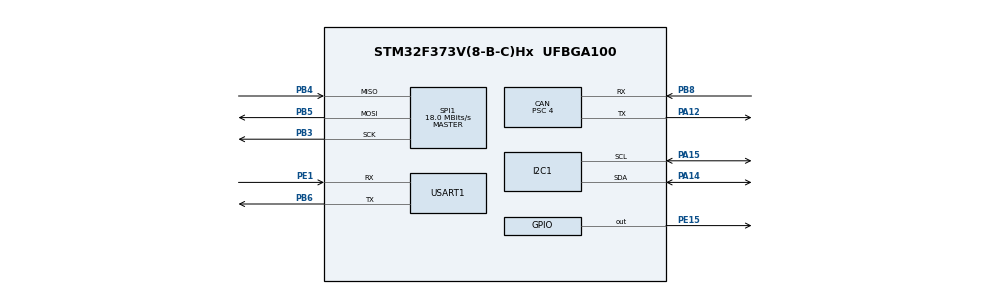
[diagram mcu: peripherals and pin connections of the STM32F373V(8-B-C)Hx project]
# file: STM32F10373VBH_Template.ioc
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CAN.BS1=CAN_BS1_5TQ
CAN.BS2=CAN_BS2_3TQ
CAN.CalculateBaudRate=1000000
CAN.CalculateTimeBit=999.99
CAN.CalculateTimeQuantum=111.11111111111111
CAN.Prescaler=4
Mcu.Family=STM32F3
Mcu.Name=STM32F373V(8-B-C)Hx
Mcu.Package=UFBGA100
NVIC.CAN_RX0_IRQn=true\:0\:0\:false\:false\:true\:true\:true
NVIC.PriorityGroup=NVIC_PRIORITYGROUP_4
NVIC.TIM2_IRQn=true\:0\:0\:false\:false\:true\:true\:true
NVIC.USART1_IRQn=true\:0\:0\:false\:false\:true\:true\:true
PA12.Mode=CAN_Activate
PA12.Signal=CAN_TX
PA14.Mode=I2C
PA14.Signal=I2C1_SDA
PA15.Mode=I2C
PA15.Signal=I2C1_SCL
PB3.Mode=Full_Duplex_Master
PB3.Signal=SPI1_SCK
PB4.Mode=Full_Duplex_Master
PB4.Signal=SPI1_MISO
PB5.Mode=Full_Duplex_Master
PB5.Signal=SPI1_MOSI
PB6.Mode=Asynchronous
PB6.Signal=USART1_TX
PB8.Mode=CAN_Activate
PB8.Signal=CAN_RX
PE1.Mode=Asynchronous
PE1.Signal=USART1_RX
PE15.GPIO_Speed=GPIO_SPEED_FREQ_HIGH
PE15.Signal=GPIO_Output
PF0-OSC_IN.Mode=HSE-External-Oscillator
PF0-OSC_IN.Signal=RCC_OSC_IN
PF1-OSC_OUT.Mode=HSE-External-Oscillator
PF1-OSC_OUT.Signal=RCC_OSC_OUT
ProjectManager.HeapSize=0x200
ProjectManager.StackSize=0x400
ProjectManager.TargetToolchain=Makefile
RCC.AHBFreq_Value=72000000
RCC.APB1CLKDivider=RCC_HCLK_DIV2
RCC.APB1Freq_Value=36000000
RCC.APB1TimFreq_Value=72000000
RCC.APB2Freq_Value=36000000
RCC.APB2TimFreq_Value=72000000
RCC.CortexFreq_Value=72000000
RCC.HCLKFreq_Value=72000000
RCC.HSE_VALUE=8000000
RCC.HSI_VALUE=8000000
RCC.LSE_VALUE=32768
RCC.PLLMUL=RCC_PLL_MUL9
RCC.PLLSourceVirtual=RCC_PLLSOURCE_HSE
RCC.SYSCLKFreq_VALUE=72000000
RCC.SYSCLKSource=RCC_SYSCLKSOURCE_PLLCLK
RCC.USBFreq_Value=72000000
SPI1.CalculateBaudRate=18.0 MBits/s
SPI1.Direction=SPI_DIRECTION_2LINES
SPI1.Mode=SPI_MODE_MASTER
SPI1.VirtualType=VM_MASTER
TIM2.Period=999
TIM2.Prescaler=35
USART1.VirtualMode-Asynchronous=VM_ASYNC
VP_TIM2_VS_ClockSourceINT.Mode=Internal
board=custom

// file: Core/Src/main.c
/* USER CODE BEGIN Header */
/**
  ******************************************************************************
  * @file           : main.c
  * @brief          : Main program body
  ******************************************************************************
  * @attention
  *
  * <h2><center>&copy; Copyright (c) 2021 STMicroelectronics.
  * All rights reserved.</center></h2>
  *
  * This software component is licensed by ST under BSD 3-Clause license,
  * the "License"; You may not use this file except in compliance with the
  * License. You may obtain a copy of the License at:
  *                        opensource.org/licenses/BSD-3-Clause
  *
  ******************************************************************************
  */
/* USER CODE END Header */
#include "main.h"

CAN_HandleTypeDef hcan;

I2C_HandleTypeDef hi2c1;

SPI_HandleTypeDef hspi1;

TIM_HandleTypeDef htim2;

UART_HandleTypeDef huart1;

void SystemClock_Config(void);
static void MX_GPIO_Init(void);
static void MX_CAN_Init(void);
static void MX_I2C1_Init(void);
static void MX_SPI1_Init(void);
static void MX_TIM2_Init(void);
static void MX_USART1_UART_Init(void);

int main(void)
{

  /* MCU Configuration--------------------------------------------------------*/

  /* Reset of all peripherals, Initializes the Flash interface and the Systick. */
  HAL_Init();

  /* Configure the system clock */
  SystemClock_Config();

  /* Initialize all configured peripherals */
  MX_GPIO_Init();
  MX_CAN_Init();
  MX_I2C1_Init();
  MX_SPI1_Init();
  MX_TIM2_Init();
  MX_USART1_UART_Init();

  /* Infinite loop */
  while (1)
  {

  }
}

void SystemClock_Config(void)
{
  RCC_OscInitTypeDef RCC_OscInitStruct = {0};
  RCC_ClkInitTypeDef RCC_ClkInitStruct = {0};
  RCC_PeriphCLKInitTypeDef PeriphClkInit = {0};

  /** Initializes the RCC Oscillators according to the specified parameters
  * in the RCC_OscInitTypeDef structure.
  */
  RCC_OscInitStruct.OscillatorType = RCC_OSCILLATORTYPE_HSI|RCC_OSCILLATORTYPE_HSE;
  RCC_OscInitStruct.HSEState = RCC_HSE_ON;
  RCC_OscInitStruct.HSEPredivValue = RCC_HSE_PREDIV_DIV1;
  RCC_OscInitStruct.HSIState = RCC_HSI_ON;
  RCC_OscInitStruct.HSICalibrationValue = RCC_HSICALIBRATION_DEFAULT;
  RCC_OscInitStruct.PLL.PLLState = RCC_PLL_ON;
  RCC_OscInitStruct.PLL.PLLSource = RCC_PLLSOURCE_HSE;
  RCC_OscInitStruct.PLL.PLLMUL = RCC_PLL_MUL9;
  if (HAL_RCC_OscConfig(&RCC_OscInitStruct) != HAL_OK)
  {
    Error_Handler();
  }
  /** Initializes the CPU, AHB and APB buses clocks
  */
  RCC_ClkInitStruct.ClockType = RCC_CLOCKTYPE_HCLK|RCC_CLOCKTYPE_SYSCLK
                              |RCC_CLOCKTYPE_PCLK1|RCC_CLOCKTYPE_PCLK2;
  RCC_ClkInitStruct.SYSCLKSource = RCC_SYSCLKSOURCE_PLLCLK;
  RCC_ClkInitStruct.AHBCLKDivider = RCC_SYSCLK_DIV1;
  RCC_ClkInitStruct.APB1CLKDivider = RCC_HCLK_DIV2;
  RCC_ClkInitStruct.APB2CLKDivider = RCC_HCLK_DIV1;

  if (HAL_RCC_ClockConfig(&RCC_ClkInitStruct, FLASH_LATENCY_2) != HAL_OK)
  {
    Error_Handler();
  }
  PeriphClkInit.PeriphClockSelection = RCC_PERIPHCLK_USART1|RCC_PERIPHCLK_I2C1;
  PeriphClkInit.Usart1ClockSelection = RCC_USART1CLKSOURCE_PCLK2;
  PeriphClkInit.I2c1ClockSelection = RCC_I2C1CLKSOURCE_HSI;
  if (HAL_RCCEx_PeriphCLKConfig(&PeriphClkInit) != HAL_OK)
  {
    Error_Handler();
  }
}

static void MX_CAN_Init(void)
{

  hcan.Instance = CAN;
  hcan.Init.Prescaler = 4;
  hcan.Init.Mode = CAN_MODE_NORMAL;
  hcan.Init.SyncJumpWidth = CAN_SJW_1TQ;
  hcan.Init.TimeSeg1 = CAN_BS1_5TQ;
  hcan.Init.TimeSeg2 = CAN_BS2_3TQ;
  hcan.Init.TimeTriggeredMode = DISABLE;
  hcan.Init.AutoBusOff = DISABLE;
  hcan.Init.AutoWakeUp = DISABLE;
  hcan.Init.AutoRetransmission = DISABLE;
  hcan.Init.ReceiveFifoLocked = DISABLE;
  hcan.Init.TransmitFifoPriority = DISABLE;
  if (HAL_CAN_Init(&hcan) != HAL_OK)
  {
    Error_Handler();
  }

}

static void MX_I2C1_Init(void)
{

  hi2c1.Instance = I2C1;
  hi2c1.Init.Timing = 0x2000090E;
  hi2c1.Init.OwnAddress1 = 0;
  hi2c1.Init.AddressingMode = I2C_ADDRESSINGMODE_7BIT;
  hi2c1.Init.DualAddressMode = I2C_DUALADDRESS_DISABLE;
  hi2c1.Init.OwnAddress2 = 0;
  hi2c1.Init.OwnAddress2Masks = I2C_OA2_NOMASK;
  hi2c1.Init.GeneralCallMode = I2C_GENERALCALL_DISABLE;
  hi2c1.Init.NoStretchMode = I2C_NOSTRETCH_DISABLE;
  if (HAL_I2C_Init(&hi2c1) != HAL_OK)
  {
    Error_Handler();
  }
  /** Configure Analogue filter
  */
  if (HAL_I2CEx_ConfigAnalogFilter(&hi2c1, I2C_ANALOGFILTER_ENABLE) != HAL_OK)
  {
    Error_Handler();
  }
  /** Configure Digital filter
  */
  if (HAL_I2CEx_ConfigDigitalFilter(&hi2c1, 0) != HAL_OK)
  {
    Error_Handler();
  }

}

static void MX_SPI1_Init(void)
{

  /* SPI1 parameter configuration*/
  hspi1.Instance = SPI1;
  hspi1.Init.Mode = SPI_MODE_MASTER;
  hspi1.Init.Direction = SPI_DIRECTION_2LINES;
  hspi1.Init.DataSize = SPI_DATASIZE_4BIT;
  hspi1.Init.CLKPolarity = SPI_POLARITY_LOW;
  hspi1.Init.CLKPhase = SPI_PHASE_1EDGE;
  hspi1.Init.NSS = SPI_NSS_SOFT;
  hspi1.Init.BaudRatePrescaler = SPI_BAUDRATEPRESCALER_2;
  hspi1.Init.FirstBit = SPI_FIRSTBIT_MSB;
  hspi1.Init.TIMode = SPI_TIMODE_DISABLE;
  hspi1.Init.CRCCalculation = SPI_CRCCALCULATION_DISABLE;
  hspi1.Init.CRCPolynomial = 7;
  hspi1.Init.CRCLength = SPI_CRC_LENGTH_DATASIZE;
  hspi1.Init.NSSPMode = SPI_NSS_PULSE_ENABLE;
  if (HAL_SPI_Init(&hspi1) != HAL_OK)
  {
    Error_Handler();
  }

}

static void MX_TIM2_Init(void)
{

  TIM_ClockConfigTypeDef sClockSourceConfig = {0};
  TIM_MasterConfigTypeDef sMasterConfig = {0};

  htim2.Instance = TIM2;
  htim2.Init.Prescaler = 35;
  htim2.Init.CounterMode = TIM_COUNTERMODE_UP;
  htim2.Init.Period = 999;
  htim2.Init.ClockDivision = TIM_CLOCKDIVISION_DIV1;
  htim2.Init.AutoReloadPreload = TIM_AUTORELOAD_PRELOAD_DISABLE;
  if (HAL_TIM_Base_Init(&htim2) != HAL_OK)
  {
    Error_Handler();
  }
  sClockSourceConfig.ClockSource = TIM_CLOCKSOURCE_INTERNAL;
  if (HAL_TIM_ConfigClockSource(&htim2, &sClockSourceConfig) != HAL_OK)
  {
    Error_Handler();
  }
  sMasterConfig.MasterOutputTrigger = TIM_TRGO_RESET;
  sMasterConfig.MasterSlaveMode = TIM_MASTERSLAVEMODE_DISABLE;
  if (HAL_TIMEx_MasterConfigSynchronization(&htim2, &sMasterConfig) != HAL_OK)
  {
    Error_Handler();
  }

}

static void MX_USART1_UART_Init(void)
{

  huart1.Instance = USART1;
  huart1.Init.BaudRate = 38400;
  huart1.Init.WordLength = UART_WORDLENGTH_8B;
  huart1.Init.StopBits = UART_STOPBITS_1;
  huart1.Init.Parity = UART_PARITY_NONE;
  huart1.Init.Mode = UART_MODE_TX_RX;
  huart1.Init.HwFlowCtl = UART_HWCONTROL_NONE;
  huart1.Init.OverSampling = UART_OVERSAMPLING_16;
  huart1.Init.OneBitSampling = UART_ONE_BIT_SAMPLE_DISABLE;
  huart1.AdvancedInit.AdvFeatureInit = UART_ADVFEATURE_NO_INIT;
  if (HAL_UART_Init(&huart1) != HAL_OK)
  {
    Error_Handler();
  }

}

static void MX_GPIO_Init(void)
{
  GPIO_InitTypeDef GPIO_InitStruct = {0};

  /* GPIO Ports Clock Enable */
  __HAL_RCC_GPIOE_CLK_ENABLE();
  __HAL_RCC_GPIOB_CLK_ENABLE();
  __HAL_RCC_GPIOA_CLK_ENABLE();
  __HAL_RCC_GPIOF_CLK_ENABLE();

  /*Configure GPIO pin Output Level */
  HAL_GPIO_WritePin(GPIOE, GPIO_PIN_15, GPIO_PIN_RESET);

  /*Configure GPIO pin : PE15 */
  GPIO_InitStruct.Pin = GPIO_PIN_15;
  GPIO_InitStruct.Mode = GPIO_MODE_OUTPUT_PP;
  GPIO_InitStruct.Pull = GPIO_NOPULL;
  GPIO_InitStruct.Speed = GPIO_SPEED_FREQ_HIGH;
  HAL_GPIO_Init(GPIOE, &GPIO_InitStruct);

}

void Error_Handler(void)
{
  __disable_irq();
  while (1)
  {
  }
}

/************************ (C) COPYRIGHT STMicroelectronics *****END OF FILE****/
